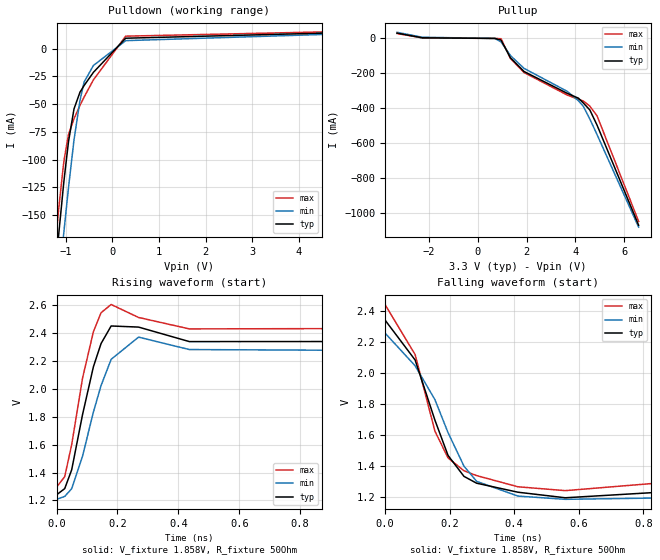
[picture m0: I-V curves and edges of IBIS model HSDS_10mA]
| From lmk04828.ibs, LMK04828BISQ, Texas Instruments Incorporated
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[Model]   HSDS_10mA
Model_type   Output
Polarity   Non-Inverting
Vmeas = 1.9
Vref = 1.9
Cref = 0pF
Rref = 50
|   typ   min   max
|   (nom PVT)   (slow PVT)   (fast PVT)
C_comp   2.777p   2.653p   2.902p
|C_comp (high state)   5.673p   4.718p   5.673p
|C_comp (low state)   2.777p   2.653p   2.902p
| Where   nom PVT is  Nominal Process, 3.3V, 27C
|   Fast PVT is Strong Process, 3.45V, -40C
|   Slow PVT is Weak Process, 3.15V, 125C
[Voltage Range]   3.3   3.15   3.45
[Temperature Range]   27   125   -40
[Pullup Reference]   3.3   3.15   3.45
[Pulldown Reference]   0   0   -0
[Power Clamp Reference]   3.3   3.15   3.45
[GND Clamp Reference]   0   0   0
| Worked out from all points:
|   slope of the pulldown table from 0 to 0.495 V, typ, clamps not added: 41.5 ohm
|   slope of the pullup table from 0 to 0.495 V, typ, clamps not added: 12.9 kohm
|   falling waveform, V_fixture 1.858V, R_fixture 50Ohm: 20-80 % time 116ps typ, 147ps min, 98.6ps max; typ from 2.34 V to 1.24 V
|   rising waveform, V_fixture 1.858V, R_fixture 50Ohm: 20-80 % time 62.3ps typ, 76.7ps min, 54.4ps max; typ from 1.24 V to 2.34 V
[Pulldown]
|   Voltage   I(typ)   I(min)   I(max)
-3.3V     -1.221A    -1.195A    -1.249A
-1.241V   -207.1mA   -250.6mA   -184.1mA
-1.152V   -166.7mA   -211.8mA   -143.8mA
-1.053V   -124.2mA   -169.6mA   -105.3mA
-1.033V   -116.2mA   -161.4mA   -98.96mA
-943.8mV  -84.03mA   -125.4mA   -77.43mA
-825mV    -54.22mA   -82.15mA   -63.11mA
-696.3mV  -39.16mA   -46.45mA   -51.06mA
-607.2mV  -33.16mA   -29.96mA   -43.52mA
-409.2mV  -21.36mA   -15.19mA   -28.15mA
283.8mV   9.398mA    7.213mA    11.25mA
6.59V     16.22mA    15.52mA    16.96mA
[Pullup]
|   Voltage   I(typ)   I(min)   I(max)
-3.3V     30.58mA    35.18mA    28.21mA
-2.27V    3.792mA    7.025mA    3.033mA
699.6mV   185.9uA    51.87uA    228.9uA
957mV     -9.234mA   -19.95mA   -1.603mA
1.343V    -111.3mA   -98.35mA   -115.3mA
1.897V    -189.5mA   -171.7mA   -195.4mA
3.67V     -315.3mA   -303.7mA   -325.1mA
4.125V    -342.8mA   -357.4mA   -348.9mA
4.323V    -370mA     -389mA     -358.8mA
4.59V     -409.9mA   -461.9mA   -388mA
4.887V    -497.2mA   -551.7mA   -443.9mA
6.59V     -1.072A    -1.083A    -1.05A
[Ramp]
R_load = 50
|   typ   min   max
dV/dt_r   0.660787/6.23189e-11   0.62932/7.6652e-11   0.687252/5.44213e-11
dV/dt_f   0.660787/1.15699e-10   0.62932/1.46839e-10   0.687252/9.8568e-11
[Falling Waveform]
V_fixture = 1.858V
V_fixture_min = 1.79V
V_fixture_max = 1.948V
R_fixture = 50Ohm
C_fixture = 0F
|   Time   V(typ)   V(min)   V(max)
|   0   2.34084   2.25715   2.4407
|   1.74166e-10   2.34095   2.25841   2.44087
|   1.7438e-10   2.34097   2.25841   2.44087
|   2.27196e-10   2.3448   2.25879   2.44606
|   2.39297e-10   2.34385   2.25888   2.44725
|   2.40153e-10   2.34378   2.25879   2.44733
|   2.42677e-10   2.34358   2.25851   2.44594
|   2.46149e-10   2.34099   2.25813   2.44402
|   2.46577e-10   2.34067   2.258   2.44379
|   2.53e-10   2.33586   2.25605   2.43372
|   2.55309e-10   2.33226   2.25437   2.42575
|   2.57653e-10   2.32784   2.25267   2.41766
|   2.58991e-10   2.32531   2.25095   2.41304
|   2.59927e-10   2.32354   2.24974   2.4092
|   2.6596e-10   2.30759   2.24198   2.38449
|   2.71853e-10   2.28663   2.23439   2.36034
|   2.7442e-10   2.27749   2.22912   2.34983
|   2.75114e-10   2.27502   2.2277   2.34729
|   2.81637e-10   2.25182   2.21165   2.32341
|   2.84934e-10   2.24009   2.20168   2.31135
|   2.93345e-10   2.21017   2.17625   2.28793
|   2.94949e-10   2.20446   2.17141   2.28476
|   3.08866e-10   2.16895   2.12933   2.25725
|   3.10168e-10   2.16625   2.1254   2.25468
|   3.11524e-10   2.16344   2.1213   2.25228
|   3.15048e-10   2.15613   2.11278   2.24603
|   3.24808e-10   2.1359   2.0892   2.21997
|   3.31676e-10   2.12166   2.07261   2.18546
|   3.33293e-10   2.1183   2.06921   2.17734
|   3.4218e-10   2.08994   2.05052   2.13269
|   3.44233e-10   2.08339   2.04621   2.11815
|   3.47203e-10   2.06851   2.03996   2.09713
|   3.53556e-10   2.03667   2.0266   2.04604
|   3.57248e-10   2.01816   2.01539   2.01635
|   3.62271e-10   1.99298   2.00013   1.97208
|   3.64463e-10   1.982   1.99347   1.95226
|   3.72317e-10   1.92861   1.96961   1.88125
|   3.78429e-10   1.88706   1.95105   1.83015
|   3.88138e-10   1.82107   1.90692   1.74898
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0s        2.341V     2.257V     2.441V
93.26ps   2.083V     2.046V     2.118V
154.4ps   1.696V     1.828V     1.625V
195.1ps   1.468V     1.615V     1.452V
244.4ps   1.333V     1.399V     1.369V
283.6ps   1.289V     1.301V     1.338V
411.2ps   1.231V     1.206V     1.266V
557.9ps   1.195V     1.185V     1.241V
891.2ps   1.236V     1.195V     1.298V
2.749ns   1.24V      1.208V     1.295V
[Rising Waveform]
V_fixture = 1.858V
V_fixture_min = 1.79V
V_fixture_max = 1.948V
R_fixture = 50Ohm
C_fixture = 0F
|   Time   V(typ)   V(min)   V(max)
|   0   1.23953   1.20829   1.29528
|   2.12421e-10   1.23906   1.20918   1.29513
|   2.18452e-10   1.24079   1.20921   1.29512
|   2.23103e-10   1.24211   1.20923   1.29832
|   2.27196e-10   1.24328   1.21082   1.30114
|   2.30647e-10   1.24705   1.21217   1.30351
|   2.39297e-10   1.2565   1.21554   1.31913
|   2.40153e-10   1.25744   1.2162   1.32067
|   2.42677e-10   1.26019   1.21816   1.32864
|   2.46149e-10   1.26853   1.22085   1.3396
|   2.46577e-10   1.26956   1.22133   1.34095
|   2.53e-10   1.285   1.22858   1.37144
|   2.55309e-10   1.29325   1.23286   1.38921
|   2.58991e-10   1.30834   1.23969   1.41755
|   2.59927e-10   1.31217   1.24142   1.42602
|   2.64671e-10   1.33782   1.25022   1.46897
|   2.65596e-10   1.34282   1.25275   1.47734
|   2.6596e-10   1.34478   1.25374   1.48124
|   2.67837e-10   1.35893   1.25888   1.50136
|   2.71853e-10   1.3892   1.26987   1.54882
|   2.72317e-10   1.3927   1.27145   1.5543
|   2.7442e-10   1.40855   1.27863   1.58111
|   2.75114e-10   1.41379   1.281   1.59042
|   2.75776e-10   1.41877   1.28377   1.59929
|   2.78626e-10   1.44676   1.29572   1.63749
|   2.80728e-10   1.46742   1.30453   1.66675
|   2.81637e-10   1.47635   1.30834   1.67963
|   2.84511e-10   1.50457   1.32513   1.72035
|   2.8799e-10   1.54296   1.34545   1.76965
|   2.93345e-10   1.60564   1.37674   1.84553
|   2.94683e-10   1.6213   1.38455   1.86268
|   3.08866e-10   1.78732   1.49709   2.04455
|   3.10168e-10   1.80123   1.50742   2.06125
|   3.11524e-10   1.81572   1.51818   2.07665
|   3.15048e-10   1.85337   1.5501   2.11665
|   3.24808e-10   1.95766   1.6385   2.21787
|   3.27823e-10   1.98988   1.66581   2.24455
|   3.31676e-10   2.02667   1.70071   2.27864
|   3.33293e-10   2.04211   1.71463   2.29294
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0s        1.24V      1.208V     1.295V
26.91ps   1.285V     1.229V     1.371V
49.69ps   1.419V     1.284V     1.599V
85.43ps   1.816V     1.518V     2.077V
121.1ps   2.159V     1.834V     2.41V
146.2ps   2.325V     2.024V     2.546V
179.3ps   2.451V     2.212V     2.605V
269.3ps   2.443V     2.371V     2.512V
436.1ps   2.339V     2.282V     2.43V
2.774ns   2.341V     2.257V     2.441V
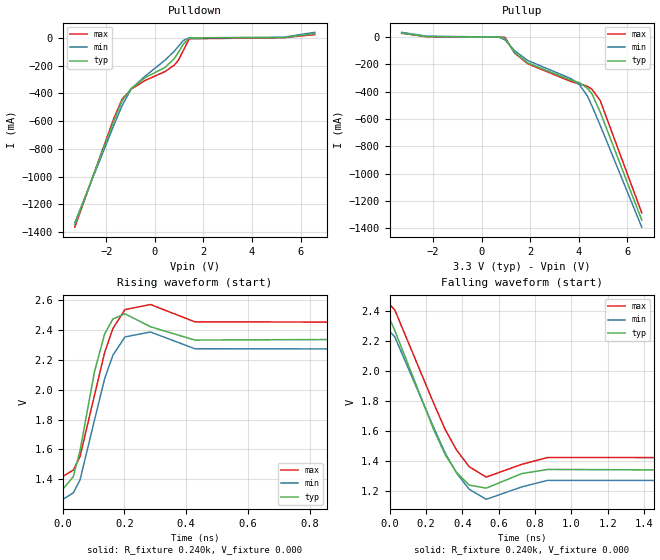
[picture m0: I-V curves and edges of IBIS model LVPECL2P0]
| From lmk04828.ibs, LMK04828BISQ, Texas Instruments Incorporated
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[Model]   LVPECL2P0
Model_type   Output
Polarity   Non-Inverting
Vmeas = 1.65
Vref = 0
Cref = 0pF
Rref = 50
|   typ   min   max
|   (nom PVT)   (slow PVT)   (fast PVT)
C_comp   1.835p   1.792p   2.242p
|C_comp (hi state)   3.662p   3.340p   4.506p
|C_comp (low state)   1.835p   1.792p   2.242p
| Where   nom PVT is  Nominal Process, 3.3V, 27C
|   Fast PVT is Strong Process, 3.45V, -40C
|   Slow PVT is Weak Process, 3.15V, 125C
[Voltage Range]   3.3   3.15   3.45
[Temperature Range]   27   125   -40
[Pullup Reference]   3.3   3.15   3.45
[Pulldown Reference]   0   0   0
[Power Clamp Reference]   3.3   3.15   3.45
[GND Clamp Reference]   0   0   0
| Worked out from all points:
|   slope of the pulldown table from 0 to 0.495 V, typ, clamps not added: 9.79 ohm
|   slope of the pullup table from 0 to 0.495 V, typ, clamps not added: 36.6 kohm
|   falling waveform, R_fixture 0.240k, V_fixture 0.000: 20-80 % time 200ps typ, 219ps min, 219ps max; typ from 2.35 V to 1.33 V
|   rising waveform, R_fixture 0.240k, V_fixture 0.000: 20-80 % time 55.1ps typ, 68.3ps min, 68.3ps max; typ from 1.33 V to 2.35 V
[Pulldown]
|   Voltage   I(typ)   I(min)   I(max)
-3.3V     -1.347A    -1.333A    -1.365A
-1.696V   -601.3mA   -632.2mA   -583mA
-1.35V    -453.6mA   -488.4mA   -441.7mA
-973.5mV  -364.8mA   -367.8mA   -370.1mA
-409.2mV  -287.7mA   -277.2mA   -307.9mA
422.4mV   -212.8mA   -160.4mA   -242.8mA
798.6mV   -149.4mA   -96.27mA   -196.9mA
966.9mV   -105.9mA   -61.97mA   -161.7mA
1.175V    -44.34mA   -18.43mA   -90.58mA
1.412V    -406.3uA   -173.6uA   -6.751mA
5.293V    1.965mA    4.249mA    908.8uA
6.59V     30.2mA     39.73mA    23.76mA
[Pullup]
|   Voltage   I(typ)   I(min)   I(max)
-3.3V     30.41mA    35.01mA    27.91mA
-2.27V    3.542mA    6.838mA    2.762mA
699.6mV   56.39uA    -63.38uA   84.88uA
957mV     -9.329mA   -20.04mA   -1.724mA
1.343V    -111.4mA   -98.42mA   -115.4mA
1.897V    -189.5mA   -171.7mA   -195.5mA
3.679V    -315.9mA   -304.6mA   -325.7mA
4.026V    -334mA     -349mA     -344mA
4.353V    -375.2mA   -432.1mA   -360.6mA
4.541V    -416.5mA   -505mA     -382.9mA
4.877V    -548.9mA   -645.9mA   -464.4mA
6.59V     -1.341A    -1.393A    -1.288A
[Ramp]
R_load = 240
|   typ   min   max
dV/dt_r   0.610344/5.51243e-11   0.599049/6.83253e-11   0.616554/4.88704e-11
dV/dt_f   0.610239/1.9958e-10   0.599001/2.18888e-10   0.616426/1.7983e-10
[Falling Waveform]
R_fixture = 0.240k
V_fixture = 0.000
V_fixture_min = 0.000
V_fixture_max = 0.000
C_fixture = 0.000
|  time   V(typ)   V(min)   V(max)
0s        2.349V     2.265V     2.445V
28.02ps   2.272V     2.229V     2.409V
241.5ps   1.61V      1.624V     1.786V
306.9ps   1.437V     1.447V     1.605V
369.8ps   1.318V     1.314V     1.468V
438.1ps   1.236V     1.208V     1.359V
531.3ps   1.216V     1.141V     1.29V
726.7ps   1.313V     1.224V     1.375V
869.6ps   1.341V     1.268V     1.421V
2.746ns   1.332V     1.266V     1.419V
[Rising Waveform]
R_fixture = 0.240k
V_fixture = 0.000
V_fixture_min = 0.000
V_fixture_max = 0.000
C_fixture = 0.000
|  time   V(typ)   V(min)   V(max)
0s        1.333V     1.266V     1.419V
34.23ps   1.418V     1.309V     1.462V
55.93ps   1.592V     1.397V     1.553V
103ps     2.123V     1.798V     1.965V
135.9ps   2.374V     2.075V     2.25V
162.4ps   2.473V     2.23V      2.409V
201.6ps   2.508V     2.353V     2.536V
284.2ps   2.421V     2.386V     2.57V
428ps     2.332V     2.274V     2.454V
2.774ns   2.35V      2.265V     2.445V
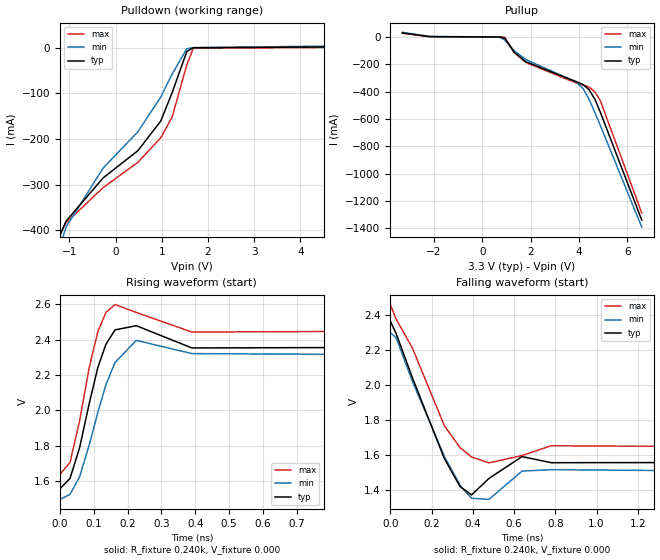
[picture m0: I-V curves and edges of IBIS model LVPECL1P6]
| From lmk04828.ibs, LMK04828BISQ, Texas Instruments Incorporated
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[Model]   LVPECL1P6
Model_type   Output
Polarity   Non-Inverting
Vmeas = 1.65
Vref = 0
Cref = 0pF
Rref = 50
|   typ   min   max
|   (nom PVT)   (slow PVT)   (fast PVT)
C_comp   1.835p   1.773p   1.921p
|C_comp (hi state)   3.662p   3.340p   4.662p
|C_comp (low state)   1.835p   1.773p   1.921p
| Where   nom PVT is  Nominal Process, 3.3V, 27C
|   Fast PVT is Strong Process, 3.45V, -40C
|   Slow PVT is Weak Process, 3.15V, 125C
[Voltage Range]   3.3   3.15   3.45
[Temperature Range]   27   125   -40
[Pullup Reference]   3.3   3.15   3.45
[Pulldown Reference]   0   0   0
[Power Clamp Reference]   3.3   3.15   3.45
[GND Clamp Reference]   0   0   0
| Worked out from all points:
|   slope of the pulldown table from 0 to 0.495 V, typ, clamps not added: 11.8 ohm
|   slope of the pullup table from 0 to 0.495 V, typ, clamps not added: 36.6 kohm
|   falling waveform, R_fixture 0.240k, V_fixture 0.000: 20-80 % time 160ps typ, 167ps min, 180ps max; typ from 2.37 V to 1.56 V
|   rising waveform, R_fixture 0.240k, V_fixture 0.000: 20-80 % time 58.1ps typ, 71.1ps min, 48.9ps max; typ from 1.56 V to 2.37 V
[Pulldown]
|   Voltage   I(typ)   I(min)   I(max)
-3.3V     -1.347A    -1.333A    -1.365A
-1.488V   -510.9mA   -546mA     -491.4mA
-1.261V   -425.1mA   -455.1mA   -420.1mA
-1.073V   -380.3mA   -393.3mA   -383.7mA
-270.6mV  -285.4mA   -263.9mA   -306.7mA
481.8mV   -225.8mA   -184.3mA   -251.3mA
976.8mV   -160.9mA   -108.1mA   -197.4mA
1.224V    -98.46mA   -57.79mA   -152mA
1.541V    -8.423mA   -2.304mA   -37.38mA
1.68V     -133.8uA   -94.03uA   -1.583mA
5.323V    1.994mA    4.265mA    945uA
6.59V     29.63mA    38.96mA    23.29mA
[Pullup]
|   Voltage   I(typ)   I(min)   I(max)
-3.3V     29.84mA    34.24mA    27.44mA
-2.162V   2.581mA    4.002mA    2.062mA
699.6mV   54.18uA    -233.2uA   84.87uA
927.3mV   -8.637mA   -21.14mA   -1.172mA
1.323V    -111.9mA   -100.7mA   -114.9mA
1.808V    -181.8mA   -165.3mA   -187mA
3.897V    -327.9mA   -331.9mA   -337.8mA
4.165V    -348.4mA   -377.2mA   -351.4mA
4.412V    -385.5mA   -455.4mA   -365.6mA
4.66V     -457.9mA   -555.2mA   -402.4mA
4.877V    -550mA     -646.9mA   -465.3mA
6.59V     -1.341A    -1.392A    -1.289A
[Ramp]
R_load = 240
|   typ   min   max
dV/dt_r   0.490315/5.80946e-11   0.481877/7.11024e-11   0.492733/4.88704e-11
dV/dt_f   0.490254/1.59672e-10   0.481842/1.66881e-10   0.492733/1.7983e-10
[Falling Waveform]
R_fixture = 0.240k
V_fixture = 0.000
V_fixture_min = 0.000
V_fixture_max = 0.000
C_fixture = 0.000
|  time   V(typ)   V(min)   V(max)
0s        2.366V     2.299V     2.461V
27.99ps   2.295V     2.271V     2.377V
105.9ps   2.044V     2.024V     2.214V
261.9ps   1.578V     1.59V      1.766V
338.2ps   1.417V     1.424V     1.64V
393.6ps   1.369V     1.35V      1.587V
478.3ps   1.464V     1.344V     1.553V
638.6ps   1.589V     1.506V     1.595V
780.2ps   1.554V     1.514V     1.651V
2.746ns   1.557V     1.496V     1.639V
[Rising Waveform]
R_fixture = 0.240k
V_fixture = 0.000
V_fixture_min = 0.000
V_fixture_max = 0.000
C_fixture = 0.000
|  time   V(typ)   V(min)   V(max)
0s        1.557V     1.496V     1.639V
29.09ps   1.614V     1.524V     1.704V
57.69ps   1.789V     1.624V     1.941V
86.24ps   2.04V      1.805V     2.244V
111.6ps   2.243V     1.989V     2.446V
135.6ps   2.374V     2.145V     2.554V
162.2ps   2.455V     2.27V      2.599V
225.4ps   2.479V     2.396V     2.554V
389.9ps   2.353V     2.321V     2.443V
2.776ns   2.366V     2.299V     2.461V
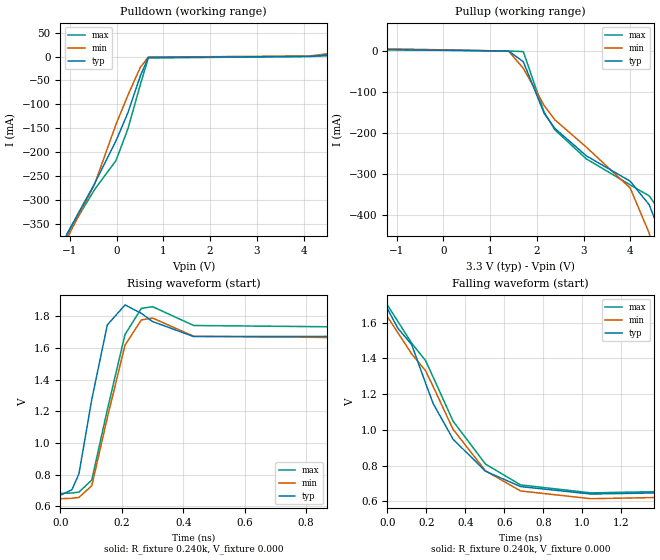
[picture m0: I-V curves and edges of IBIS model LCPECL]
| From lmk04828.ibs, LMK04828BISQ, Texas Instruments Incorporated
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[Model]   LCPECL
Model_type   Output
Polarity   Non-Inverting
Vmeas = 1.35
Vref = 0
Cref = 0pF
Rref = 50
|   typ   min   max
|   (nom PVT)   (slow PVT)   (fast PVT)
C_comp   1.056p   0.933p   1.158p
|C_comp (hi state)   1.056p   0.933p   1.158p
|C_comp (low state)   1.835p   1.764p   2.156p
| Where   nom PVT is  Nominal Process, 3.3V, 27C
|   Fast PVT is Strong Process, 3.45V, -40C
|   Slow PVT is Weak Process, 3.15V, 125C
[Voltage Range]   3.3   3.15   3.45
[Temperature Range]   27   125   -40
[Pullup Reference]   3.3   3.15   3.45
[Pulldown Reference]   0   0   0
[Power Clamp Reference]   3.3   3.15   3.45
[GND Clamp Reference]   0   0   0
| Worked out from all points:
|   slope of the pulldown table from 0 to 0.495 V, typ, clamps not added: 3.83 ohm
|   slope of the pullup table from 0 to 0.495 V, typ, clamps not added: 36.6 kohm
|   falling waveform, R_fixture 0.240k, V_fixture 0.000: 20-80 % time 268ps typ, 321ps min, 321ps max; typ from 1.68 V to 0.672 V
|   rising waveform, R_fixture 0.240k, V_fixture 0.000: 20-80 % time 51.4ps typ, 62.9ps min, 62.9ps max; typ from 0.671 V to 1.68 V
[Pulldown]
|   Voltage   I(typ)   I(min)   I(max)
-3.3V     -1.342A    -1.33A     -1.36A
-2.072V   -766.8mA   -788.7mA   -754.4mA
-1.399V   -466.8mA   -502.6mA   -448.4mA
-1.063V   -371.1mA   -381.1mA   -373.5mA
-468.6mV  -265.5mA   -266.5mA   -277.9mA
-13.2mV   -176.7mA   -142.2mA   -217.7mA
244.2mV   -117.3mA   -80.6mA    -150.8mA
511.5mV   -39.8mA    -22.12mA   -57.73mA
679.8mV   -1.977mA   -1.244mA   -3.024mA
4.145V    249.6uA    1.182mA    137.6uA
5.075V    8.277mA    12.87mA    3.792mA
6.59V     46.49mA    55.37mA    41.61mA
[Pullup]
|   Voltage   I(typ)   I(min)   I(max)
-3.3V     46.7mA     50.6mA     45.88mA
-1.617V   3.968mA    6.322mA    3.611mA
1.393V    23.73uA    -306.5uA   34.1uA
1.709V    -26.11mA   -42.06mA   -1.442mA
2.155V    -152mA     -132.9mA   -149.1mA
2.383V    -188.6mA   -167.6mA   -192mA
3.056V    -255.6mA   -234.3mA   -263mA
3.996V    -317.5mA   -334.2mA   -326.6mA
4.402V    -374.8mA   -444.1mA   -353.2mA
4.65V     -447.1mA   -544.3mA   -393.4mA
4.877V    -543.1mA   -640.6mA   -458.1mA
6.59V     -1.336A    -1.389A    -1.281A
[Ramp]
R_load = 240
|   typ   min   max
dV/dt_r   0.604822/5.13732e-11   0.590832/6.29149e-11   0.611889/4.41697e-11
dV/dt_f   0.604199/2.68061e-10   0.591674/3.21075e-10   0.611384/2.72161e-10
[Falling Waveform]
R_fixture = 0.240k
V_fixture = 0.000
V_fixture_min = 0.000
V_fixture_max = 0.000
C_fixture = 0.000
|  time   V(typ)   V(min)   V(max)
0s        1.679V     1.634V     1.7V
54.39ps   1.569V     1.544V     1.607V
125.3ps   1.477V     1.425V     1.485V
196.4ps   1.261V     1.331V     1.388V
235.9ps   1.146V     1.241V     1.294V
337.2ps   947.9mV    1.003V     1.049V
503.6ps   768.1mV    770.5mV    808.2mV
683.6ps   682.1mV    657.5mV    691.5mV
1.044ns   640.4mV    614.2mV    646.8mV
2.745ns   672.2mV    648.2mV    681.9mV
[Rising Waveform]
R_fixture = 0.240k
V_fixture = 0.000
V_fixture_min = 0.000
V_fixture_max = 0.000
C_fixture = 0.000
|  time   V(typ)   V(min)   V(max)
0s        670.9mV    648.5mV    681.9mV
37.35ps   704.9mV    651.1mV    684.5mV
60.18ps   805.8mV    656.5mV    690.2mV
102.1ps   1.277V     730.7mV    766.9mV
152.5ps   1.746V     1.159V     1.21V
210.2ps   1.873V     1.619V     1.686V
263.3ps   1.82V      1.778V     1.851V
299.9ps   1.768V     1.79V      1.862V
433.7ps   1.673V     1.675V     1.743V
2.784ns   1.679V     1.633V     1.7V
